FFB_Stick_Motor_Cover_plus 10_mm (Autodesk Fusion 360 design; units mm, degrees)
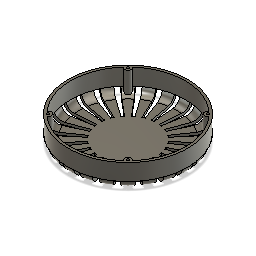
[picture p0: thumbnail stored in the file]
base_feature "Base Feature" bodies "FFB_Stick_Motor_Cover_plus 10_mm"
named bodies: "FFB_Stick_Motor_Cover_plus 10_mm"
